# FeCIM 1T1R Cell - Stub LEF for OpenLane Integration
# This is a PLACEHOLDER cell for simulation and array-level exploration.
# No physical implementation exists - technology is at TRL 4.
#
# 1T1R Architecture: 1 Transistor + 1 Resistive FeFET
# - Select transistor mitigates sneak path currents
# - Source Line (SL) provides current path control
#
# Cell Dimensions: 0.92um x 3.40um (SKY130-compatible, wider/taller)
# Usage: Array placement in FeCIM crossbar lattice generator

VERSION 5.8 ;
BUSBITCHARS "[]" ;
DIVIDERCHAR "/" ;

SITE fecim_1t1r_site
  CLASS CORE ;
  SIZE 0.92 BY 3.40 ;
  SYMMETRY X Y ;
END fecim_1t1r_site

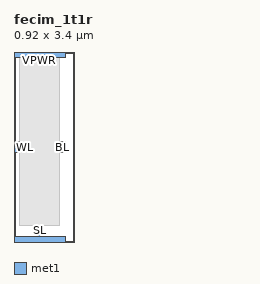
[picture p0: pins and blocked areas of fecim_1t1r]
MACRO fecim_1t1r
  CLASS CORE ;
  FOREIGN fecim_1t1r 0 0 ;
  ORIGIN 0 0 ;
  SIZE 0.92 BY 3.40 ;
  SYMMETRY X Y ;
  SITE fecim_1t1r_site ;

  PIN WL
    DIRECTION INPUT ;
    USE SIGNAL ;
    ANTENNADIFFAREA 0.0 ;
    PORT
      LAYER met1 ;
        RECT 0.000 1.600 0.100 1.800 ;
    END
  END WL

  PIN BL
    DIRECTION OUTPUT ;
    USE SIGNAL ;
    PORT
      LAYER met1 ;
        RECT 0.820 1.600 0.920 1.800 ;
    END
  END BL

  PIN SL
    DIRECTION INPUT ;
    USE SIGNAL ;
    PORT
      LAYER met1 ;
        RECT 0.410 0.100 0.510 0.300 ;
    END
  END SL

  PIN VPWR
    DIRECTION INOUT ;
    USE POWER ;
    PORT
      LAYER met1 ;
        RECT 0.000 3.300 0.920 3.400 ;
    END
  END VPWR

  PIN VGND
    DIRECTION INOUT ;
    USE GROUND ;
    PORT
      LAYER met1 ;
        RECT 0.000 0.000 0.920 0.100 ;
    END
  END VGND

  OBS
    LAYER met1 ;
      RECT 0.100 0.300 0.820 3.300 ;
  END

END fecim_1t1r

END LIBRARY
